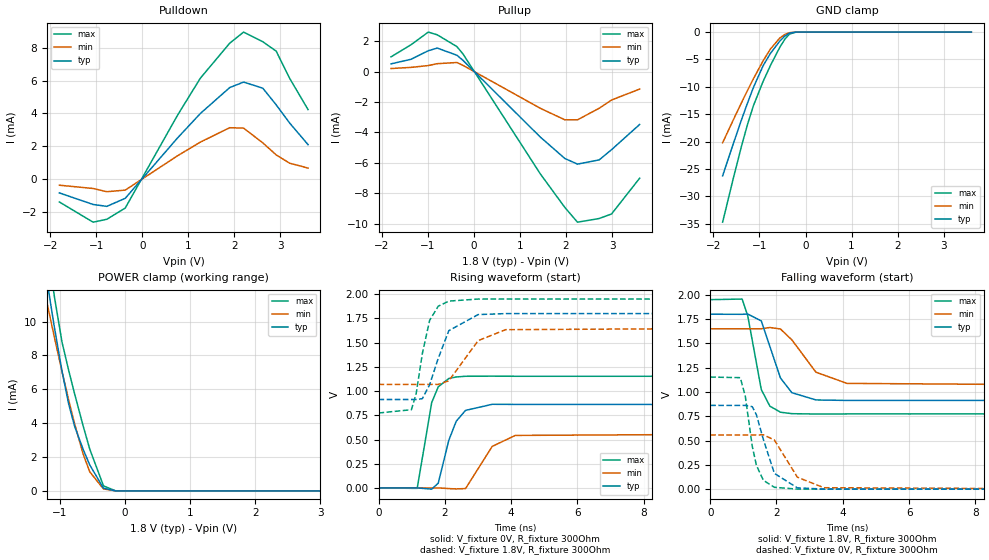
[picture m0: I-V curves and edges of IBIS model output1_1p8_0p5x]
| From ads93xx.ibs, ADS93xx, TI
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|   output1_1p8_0p5x Model
[Model]   output1_1p8_0p5x
Model_type   3-state
Polarity   Non-Inverting
Vmeas = 0.9
Vref = 0
Cref = 2pF
Rref = 100000
|   typ   min   max
C_comp   0.731pF   0.567pF   0.776pF
[Voltage Range]   1.8   1.65   1.95
[Temperature Range]   27   125   -40
[Pullup Reference]   1.8   1.65   1.95
[Pulldown Reference]   0   0   0
[Power Clamp Reference]   1.8   1.65   1.95
[GND Clamp Reference]   0   0   0
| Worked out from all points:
|   slope of the pulldown table from 0 to 0.27 V, typ, clamps not added: 300 ohm
|   slope of the pullup table from 0 to 0.27 V, typ, clamps not added: 316 ohm
|   GND clamp passes 1 mA (typ) near -0.48 V on its own axis
|   POWER clamp passes 1 mA (typ) near -0.47 V on its own axis
|   falling waveform, V_fixture 1.8V, R_fixture 300Ohm: 20-80 % time 538ps typ, 796ps min, 386ps max; typ from 1.8 V to 0.913 V
|   rising waveform, V_fixture 0V, R_fixture 300Ohm: 20-80 % time 449ps typ, 611ps min, 343ps max; typ from 0 V to 0.862 V
|   rising waveform, V_fixture 1.8V, R_fixture 300Ohm: 20-80 % time 550ps typ, 773ps min, 371ps max; typ from 0.913 V to 1.8 V
|   falling waveform, V_fixture 0V, R_fixture 300Ohm: 20-80 % time 446ps typ, 595ps min, 332ps max; typ from 0.862 V to 0 V
[Pulldown]
|   Voltage   I(typ)   I(min)   I(max)
-1.8V     -843.7uA   -375.7uA   -1.396mA
-1.066V   -1.55mA    -574.8uA   -2.628mA
-768.6mV  -1.664mA   -771uA     -2.45mA
-369mV    -1.173mA   -675.4uA   -1.765mA
765mV     2.497mA    1.413mA    3.879mA
1.262V    3.992mA    2.249mA    6.142mA
1.899V    5.57mA     3.127mA    8.272mA
2.201V    5.905mA    3.101mA    8.95mA
2.617V    5.535mA    2.206mA    8.365mA
2.909V    4.519mA    1.469mA    7.788mA
3.2V      3.415mA    967.5uA    6.139mA
3.6V      2.097mA    668uA      4.232mA
[GND Clamp]
|   Voltage   I(typ)   I(min)   I(max)
-1.8V     -26.25mA   -20.21mA   -34.72mA
-1.568V   -20.38mA   -16.03mA   -26.71mA
-1.39V    -16.01mA   -12.89mA   -20.83mA
-1.26V    -12.96mA   -10.66mA   -16.87mA
-1.13V    -10.09mA   -8.505mA   -13.41mA
-919.8mV  -6.124mA   -5.225mA   -8.988mA
-763.2mV  -3.905mA   -3.105mA   -6.125mA
-558mV    -1.639mA   -1.074mA   -2.766mA
-444.6mV  -687.9uA   -414.5uA   -1.249mA
-347.4mV  -177.3uA   -111.8uA   -351.2uA
-207mV    -3.81uA    -5.113uA   -4.887uA
3.6V      0A         0A         0A
[Pullup]
|   Voltage   I(typ)   I(min)   I(max)
-1.8V     519uA      210.2uA    977.4uA
-1.363V   819.6uA    287uA      1.78mA
-990mV    1.383mA    406.1uA    2.61mA
-795.6mV  1.559mA    529.3uA    2.431mA
-369mV    1.086mA    608uA      1.655mA
-239.4mV  758.6uA    424.4uA    1.183mA
1.445V    -4.308mA   -2.411mA   -6.737mA
1.975V    -5.711mA   -3.164mA   -8.933mA
2.25V     -6.083mA   -3.167mA   -9.906mA
2.72V     -5.805mA   -2.406mA   -9.664mA
2.99V     -5.13mA    -1.86mA    -9.363mA
3.6V      -3.47mA    -1.141mA   -7.008mA
[POWER Clamp]
|   Voltage   I(typ)   I(min)   I(max)
-1.8V     29.13mA    22.73mA    38.22mA
-1.217V   12.88mA    11.44mA    15.47mA
-1.13V    10.74mA    9.875mA    12.75mA
-1.087V   9.709mA    9.107mA    11.52mA
-968.4mV  7.078mA    7.058mA    8.793mA
-865.8mV  5.13mA     5.375mA    7.115mA
-774mV    3.808mA    3.958mA    5.725mA
-644.4mV  2.459mA    2.187mA    3.849mA
-541.8mV  1.531mA    1.127mA    2.464mA
-331.2mV  161.8uA    118.5uA    297.9uA
-142.2mV  415nA      1.1uA      356.8nA
3.6V      0A         0A         0A
[Ramp]
R_load = 300
|   typ   min   max
dV/dt_r   0.51693/4.48542e-10   0.334335/6.11186e-10   0.691708/3.43037e-10
dV/dt_f   0.532246/5.37805e-10   0.348342/7.95639e-10   0.705808/3.86079e-10
[Falling Waveform]
V_fixture = 1.8V
V_fixture_min = 1.65V
V_fixture_max = 1.95V
R_fixture = 300Ohm
C_fixture = 0F
|   Time   V(typ)   V(min)   V(max)
0s        1.8V       1.65V      1.95V
963.2ps   1.799V     1.65V      1.956V
1.134ns   1.802V     1.65V      1.782V
1.541ns   1.731V     1.65V      1.025V
1.8ns     1.469V     1.663V     853.6mV
2.119ns   1.144V     1.648V     791.5mV
2.463ns   992.3mV    1.536V     776.2mV
3.191ns   917.5mV    1.203V     772.6mV
4.126ns   912.5mV    1.088V     773.6mV
12.5ns    912.9mV    1.069V     773.7mV
[Rising Waveform]
V_fixture = 0V
V_fixture_min = 0V
V_fixture_max = 0V
R_fixture = 300Ohm
C_fixture = 0F
|   Time   V(typ)   V(min)   V(max)
0s        262.6nV    3.258uV    42.43nV
1.166ns   565.6uV    286.3uV    -4.253mV
1.604ns   -12.48mV   392.5uV    882.3mV
1.801ns   49.73mV    440.2uV    1.044V
2.119ns   491.6mV    -6.592mV   1.13V
2.341ns   687.7mV    -9.993mV   1.146V
2.624ns   800.6mV    -6.398mV   1.153V
3.429ns   863.7mV    429.2mV    1.154V
4.126ns   862.5mV    542.4mV    1.153V
12.5ns    861.6mV    557.2mV    1.153V
[Rising Waveform]
V_fixture = 1.8V
V_fixture_min = 1.65V
V_fixture_max = 1.95V
R_fixture = 300Ohm
C_fixture = 0F
|   Time   V(typ)   V(min)   V(max)
0s        913mV      1.069V     773.7mV
990.7ps   913.1mV    1.069V     807.8mV
1.134ns   913.2mV    1.069V     972.2mV
1.322ns   922.1mV    1.069V     1.389V
1.541ns   1.066V     1.069V     1.73V
1.8ns     1.337V     1.069V     1.876V
2.119ns   1.624V     1.106V     1.929V
3.005ns   1.79V      1.521V     1.95V
3.833ns   1.8V       1.634V     1.95V
12.5ns    1.8V       1.65V      1.95V
[Falling Waveform]
|Gnd
V_fixture = 0V
V_fixture_min = 0V
V_fixture_max = 0V
R_fixture = 300Ohm
C_fixture = 0F
|   Time   V(typ)   V(min)   V(max)
0s        861.6mV    557.2mV    1.153V
907.6ps   861.3mV    557.1mV    1.147V
1.059ns   861.2mV    557mV      954.8mV
1.268ns   848.3mV    557mV      443mV
1.394ns   765mV      557mV      244.5mV
1.604ns   510.6mV    558.5mV    90.31mV
1.936ns   161.7mV    505.2mV    18.14mV
2.63ns    12.45mV    122.5mV    -154.1uV
3.429ns   110.4uV    13.89mV    -934uV
12.5ns    265.7nV    3.109uV    41.91nV
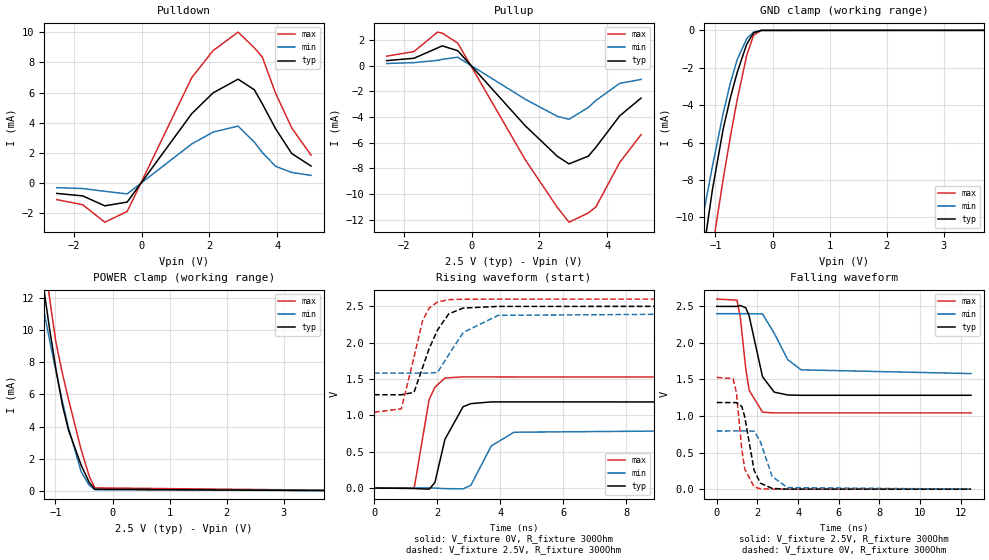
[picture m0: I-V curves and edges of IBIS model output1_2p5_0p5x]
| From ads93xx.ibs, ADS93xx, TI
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|   output1_2p5_0p5x Model
[Model]   output1_2p5_0p5x
Model_type   3-state
Polarity   Non-Inverting
Vmeas = 1.25
Vref = 0
Cref = 2pF
Rref = 100000
|   typ   min   max
C_comp   0.698pF   0.559pF   0.737pF
[Voltage Range]   2.5   2.4   2.6
[Temperature Range]   27   125   -40
[Pullup Reference]   2.5   2.4   2.6
[Pulldown Reference]   0   0   0
[Power Clamp Reference]   2.5   2.4   2.6
[GND Clamp Reference]   0   0   0
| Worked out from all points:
|   slope of the pulldown table from 0 to 0.375 V, typ, clamps not added: 301 ohm
|   slope of the pullup table from 0 to 0.375 V, typ, clamps not added: 318 ohm
|   GND clamp passes 1 mA (typ) near -0.49 V on its own axis
|   POWER clamp passes 1 mA (typ) near -0.48 V on its own axis
|   falling waveform, V_fixture 2.5V, R_fixture 300Ohm: 20-80 % time 574ps typ, 903ps min, 409ps max; typ from 2.5 V to 1.28 V
|   rising waveform, V_fixture 0V, R_fixture 300Ohm: 20-80 % time 457ps typ, 629ps min, 345ps max; typ from 0 V to 1.18 V
|   rising waveform, V_fixture 2.5V, R_fixture 300Ohm: 20-80 % time 653ps typ, 856ps min, 504ps max; typ from 1.28 V to 2.5 V
|   falling waveform, V_fixture 0V, R_fixture 300Ohm: 20-80 % time 453ps typ, 597ps min, 346ps max; typ from 1.18 V to 0 V
[Pulldown]
|   Voltage   I(typ)   I(min)   I(max)
-2.5V     -706.7uA   -326.9uA   -1.119mA
-1.735V   -870.5uA   -383.4uA   -1.458mA
-1.083V   -1.531mA   -565.4uA   -2.62mA
-422.5mV  -1.282mA   -739.7uA   -1.907mA
1.482V    4.596mA    2.586mA    6.992mA
2.112V    5.981mA    3.368mA    8.788mA
2.848V    6.889mA    3.77mA     10.02mA
3.328V    6.184mA    2.706mA    8.973mA
3.56V     5.263mA    2.023mA    8.374mA
3.958V    3.581mA    1.089mA    5.936mA
4.43V     1.946mA    688.1uA    3.652mA
5V        1.115mA    492.9uA    1.838mA
[GND Clamp]
|   Voltage   I(typ)   I(min)   I(max)
-2.5V     -44.39mA   -33.12mA   -59.46mA
-1.413V   -16.56mA   -13.29mA   -21.57mA
-1.285V   -13.54mA   -11.09mA   -17.6mA
-1.21V    -11.83mA   -9.823mA   -15.46mA
-1.052V   -8.501mA   -7.252mA   -11.64mA
-865mV    -5.281mA   -4.442mA   -7.963mA
-737.5mV  -3.589mA   -2.797mA   -5.676mA
-617.5mV  -2.236mA   -1.555mA   -3.679mA
-452.5mV  -743.8uA   -449.7uA   -1.342mA
-332.5mV  -131.9uA   -85.99uA   -263.4uA
-197.5mV  -2.745uA   -3.997uA   -3.249uA
5V        0A         0A         0A
[Pullup]
|   Voltage   I(typ)   I(min)   I(max)
-2.5V     381.6uA    158.4uA    726.9uA
-1.698V   564.8uA    223.7uA    1.085mA
-1V       1.368mA    401.6uA    2.603mA
-865mV    1.53mA     475.5uA    2.525mA
-407.5mV  1.155mA    646.2uA    1.752mA
1.587V    -4.695mA   -2.627mA   -7.343mA
2.533V    -7.072mA   -3.958mA   -11.06mA
2.877V    -7.66mA    -4.186mA   -12.2mA
3.447V    -7.055mA   -3.258mA   -11.48mA
3.672V    -6.354mA   -2.717mA   -11mA
4.37V     -3.923mA   -1.39mA    -7.552mA
5V        -2.538mA   -1.085mA   -5.385mA
[POWER Clamp]
|   Voltage   I(typ)   I(min)   I(max)
-2.5V     50.08mA    37.08mA    68.11mA
-1.292V   14.84mA    12.84mA    18.08mA
-1.248V   13.67mA    12.01mA    16.51mA
-1.202V   12.52mA    11.18mA    15mA
-1.113V   10.31mA    9.555mA    12.23mA
-992.5mV  7.585mA    7.466mA    9.256mA
-880mV    5.374mA    5.602mA    7.334mA
-775mV    3.82mA     3.973mA    5.74mA
-550mV    1.602mA    1.196mA    2.57mA
-407.5mV  524.1uA    345.2uA    909.1uA
-310mV    102.3uA    80.34uA    188.9uA
5V        0A         0A         0A
[Ramp]
R_load = 300
|   typ   min   max
dV/dt_r   0.710684/4.5657e-10   0.477432/6.29414e-10   0.917002/3.4523e-10
dV/dt_f   0.729763/5.74325e-10   0.491192/9.02866e-10   0.934183/4.09032e-10
[Falling Waveform]
V_fixture = 2.5V
V_fixture_min = 2.4V
V_fixture_max = 2.6V
R_fixture = 300Ohm
C_fixture = 0F
|   Time   V(typ)   V(min)   V(max)
0s        2.5V       2.4V       2.6V
996.2ps   2.499V     2.4V       2.585V
1.161ns   2.512V     2.4V       2.345V
1.429ns   2.481V     2.4V       1.641V
1.594ns   2.368V     2.4V       1.353V
2.249ns   1.539V     2.397V     1.053V
2.824ns   1.327V     2.133V     1.043V
3.49ns    1.288V     1.771V     1.043V
4.15ns    1.284V     1.632V     1.043V
12.5ns    1.284V     1.581V     1.043V
[Rising Waveform]
V_fixture = 0V
V_fixture_min = 0V
V_fixture_max = 0V
R_fixture = 300Ohm
C_fixture = 0F
|   Time   V(typ)   V(min)   V(max)
0s        185.4nV    3.337uV    25.93nV
1.273ns   -6.46mV    335uV      -355.7uV
1.747ns   -15.83mV   458.5uV    1.217V
1.929ns   75.11mV    -918.7uV   1.387V
2.249ns   671.4mV    -8.117mV   1.514V
2.824ns   1.119V     -11.53mV   1.529V
3.071ns   1.161V     38.38mV    1.529V
3.716ns   1.185V     577.7mV    1.529V
4.434ns   1.185V     767.8mV    1.528V
12.5ns    1.184V     795.7mV    1.528V
[Rising Waveform]
V_fixture = 2.5V
V_fixture_min = 2.4V
V_fixture_max = 2.6V
R_fixture = 300Ohm
C_fixture = 0F
|   Time   V(typ)   V(min)   V(max)
0s        1.284V     1.581V     1.043V
865.3ps   1.283V     1.581V     1.089V
1.267ns   1.316V     1.581V     1.8V
1.538ns   1.656V     1.581V     2.301V
1.747ns   1.918V     1.581V     2.477V
2.011ns   2.173V     1.59V      2.56V
2.368ns   2.396V     1.834V     2.592V
2.826ns   2.476V     2.14V      2.598V
3.937ns   2.499V     2.376V     2.599V
12.5ns    2.5V       2.4V       2.6V
[Falling Waveform]
|Gnd
V_fixture = 0V
V_fixture_min = 0V
V_fixture_max = 0V
R_fixture = 300Ohm
C_fixture = 0F
|   Time   V(typ)   V(min)   V(max)
0s        1.185V     795.7mV    1.528V
801.7ps   1.184V     796.1mV    1.513V
964.4ps   1.184V     796.2mV    1.327V
1.231ns   1.132V     796.4mV    548.6mV
1.374ns   992.6mV    796.5mV    277.5mV
1.839ns   256.5mV    794.5mV    30.06mV
2.148ns   81.42mV    645.8mV    6.216mV
2.724ns   10.15mV    173.3mV    315.9uV
3.471ns   614.1uV    21.48mV    291.8uV
12.5ns    1.223nV    3.1uV      7.163nV
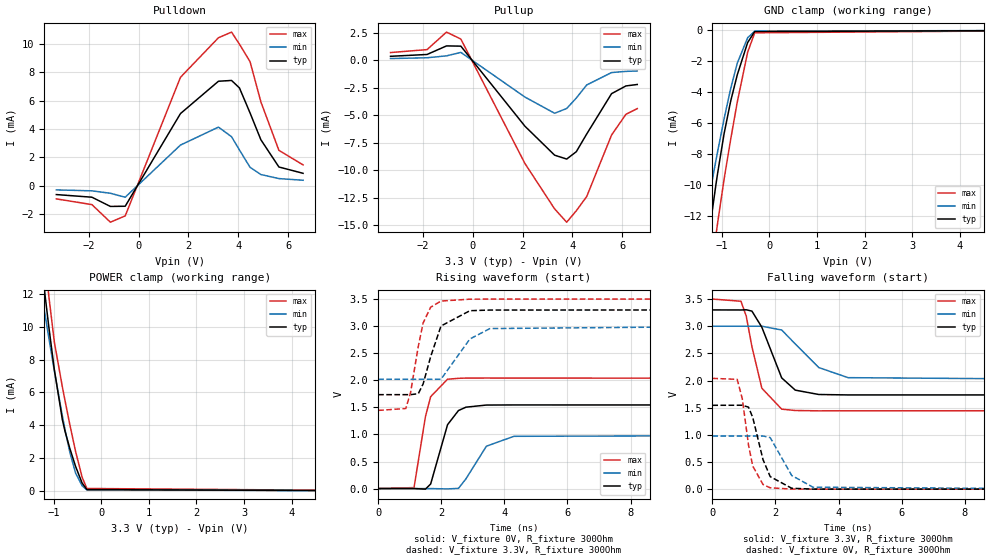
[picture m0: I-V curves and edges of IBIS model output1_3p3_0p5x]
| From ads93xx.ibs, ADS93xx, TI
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|   output1_3p3_0p5x Model
[Model]   output1_3p3_0p5x
Model_type   3-state
Polarity   Non-Inverting
Vmeas = 1.65
Vref = 0
Cref = 2pF
Rref = 100000
|   typ   min   max
C_comp   0.672pF   0.552pF   0.701pF
[Voltage Range]   3.3   3   3.5
[Temperature Range]   27   125   -40
[Pullup Reference]   3.3   3   3.5
[Pulldown Reference]   0   0   0
[Power Clamp Reference]   3.3   3   3.5
[GND Clamp Reference]   0   0   0
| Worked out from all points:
|   slope of the pulldown table from 0 to 0.495 V, typ, clamps not added: 303 ohm
|   slope of the pullup table from 0 to 0.495 V, typ, clamps not added: 320 ohm
|   GND clamp passes 1 mA (typ) near -0.49 V on its own axis
|   POWER clamp passes 1 mA (typ) near -0.48 V on its own axis
|   falling waveform, V_fixture 3.3V, R_fixture 300Ohm: 20-80 % time 634ps typ, 997ps min, 461ps max; typ from 3.3 V to 1.74 V
|   rising waveform, V_fixture 0V, R_fixture 300Ohm: 20-80 % time 478ps typ, 633ps min, 362ps max; typ from 0 V to 1.54 V
|   rising waveform, V_fixture 3.3V, R_fixture 300Ohm: 20-80 % time 488ps typ, 663ps min, 388ps max; typ from 1.74 V to 3.3 V
|   falling waveform, V_fixture 0V, R_fixture 300Ohm: 20-80 % time 431ps typ, 561ps min, 332ps max; typ from 1.54 V to 0 V
[Pulldown]
|   Voltage   I(typ)   I(min)   I(max)
-3.3V     -632.2uA   -302uA     -936.7uA
-1.874V   -818uA     -368uA     -1.34mA
-1.132V   -1.469mA   -539.8uA   -2.582mA
-537.9mV  -1.456mA   -820uA     -2.138mA
1.68V     5.087mA    2.863mA    7.648mA
3.204V    7.37mA     4.131mA    10.44mA
3.729V    7.425mA    3.454mA    10.84mA
4.046V    6.9mA      2.521mA    9.988mA
4.471V    5.137mA    1.294mA    8.757mA
4.907V    3.237mA    783.1uA    5.912mA
5.63V     1.315mA    496.8uA    2.491mA
6.6V      868.6uA    379.4uA    1.461mA
[GND Clamp]
|   Voltage   I(typ)   I(min)   I(max)
-3.3V     -65.43mA   -48.13mA   -88mA
-1.419V   -16.72mA   -13.4mA    -21.78mA
-1.34V    -14.82mA   -12.03mA   -19.27mA
-1.251V   -12.75mA   -10.51mA   -16.6mA
-1.122V   -9.915mA   -8.368mA   -13.21mA
-1.092V   -9.299mA   -7.887mA   -12.52mA
-953.7mV  -6.687mA   -5.727mA   -9.638mA
-815.1mV  -4.579mA   -3.766mA   -7.051mA
-676.5mV  -2.877mA   -2.123mA   -4.639mA
-458.7mV  -789uA     -478.5uA   -1.416mA
-310.2mV  -80.27uA   -56.11uA   -160.2uA
6.6V      0A         0A         0A
[Pullup]
|   Voltage   I(typ)   I(min)   I(max)
-3.3V     340.1uA    135.7uA    680.5uA
-1.835V   506uA      206.1uA    948.9uA
-1.053V   1.285mA    380uA      2.541mA
-478.5mV  1.263mA    695.5uA    1.908mA
2.095V    -6.018mA   -3.367mA   -9.411mA
3.284V    -8.648mA   -4.837mA   -13.53mA
3.769V    -9.001mA   -4.404mA   -14.74mA
4.155V    -8.331mA   -3.452mA   -13.7mA
4.571V    -6.727mA   -2.266mA   -12.41mA
5.57V     -3.053mA   -1.137mA   -6.814mA
6.145V    -2.355mA   -1.032mA   -4.935mA
6.6V      -2.222mA   -994uA     -4.413mA
[POWER Clamp]
|   Voltage   I(typ)   I(min)   I(max)
-3.3V     74.57mA    53.89mA    103mA
-1.241V   13.49mA    11.88mA    16.28mA
-1.171V   11.74mA    10.61mA    14mA
-1.102V   10.06mA    9.373mA    11.94mA
-983.4mV  7.392mA    7.311mA    9.076mA
-815.1mV  4.344mA    4.58mA     6.342mA
-755.7mV  3.594mA    3.689mA    5.454mA
-656.7mV  2.576mA    2.339mA    4.022mA
-537.9mV  1.498mA    1.095mA    2.414mA
-399.3mV  475.5uA    314.3uA    830.4uA
-300.3mV  81.22uA    66.3uA     149.3uA
6.6V      0A         0A         0A
[Ramp]
R_load = 300
|   typ   min   max
dV/dt_r   0.926181/4.77678e-10   0.587231/6.33037e-10   1.22401/3.625e-10
dV/dt_f   0.938833/6.3376e-10   0.58887/9.96938e-10   1.23355/4.60705e-10
[Falling Waveform]
V_fixture = 3.3V
V_fixture_min = 3V
V_fixture_max = 3.5V
R_fixture = 300Ohm
C_fixture = 0F
|   Time   V(typ)   V(min)   V(max)
0s        3.3V       3V         3.5V
907.2ps   3.299V     3V         3.46V
1.074ns   3.303V     3V         3.186V
1.254ns   3.278V     3V         2.624V
1.569ns   2.981V     3V         1.858V
2.198ns   2.048V     2.93V      1.473V
2.629ns   1.823V     2.673V     1.448V
3.373ns   1.743V     2.239V     1.442V
4.301ns   1.735V     2.053V     1.443V
12.5ns    1.735V     2.019V     1.444V
[Rising Waveform]
V_fixture = 0V
V_fixture_min = 0V
V_fixture_max = 0V
R_fixture = 300Ohm
C_fixture = 0F
|   Time   V(typ)   V(min)   V(max)
0s        256nV      3.162uV    8.412nV
1.136ns   797.2uV    298.3uV    18.14mV
1.498ns   -10.86mV   392.5uV    1.331V
1.663ns   85.15mV    435.3uV    1.698V
2.198ns   1.18V      -6.358mV   2.02V
2.545ns   1.442V     4.149mV    2.037V
2.783ns   1.504V     180.9mV    2.041V
3.429ns   1.543V     782.8mV    2.042V
4.301ns   1.545V     965.6mV    2.041V
12.5ns    1.544V     978.7mV    2.04V
[Rising Waveform]
V_fixture = 3.3V
V_fixture_min = 3V
V_fixture_max = 3.5V
R_fixture = 300Ohm
C_fixture = 0F
|   Time   V(typ)   V(min)   V(max)
0s        1.735V     2.019V     1.444V
874.7ps   1.735V     2.019V     1.479V
1.024ns   1.735V     2.019V     1.769V
1.271ns   1.753V     2.019V     2.627V
1.424ns   1.933V     2.019V     3.06V
1.663ns   2.437V     2.019V     3.35V
1.99ns    3.003V     2.02V      3.464V
2.907ns   3.286V     2.764V     3.499V
3.54ns    3.298V     2.956V     3.501V
12.5ns    3.3V       3V         3.5V
[Falling Waveform]
|Gnd
V_fixture = 0V
V_fixture_min = 0V
V_fixture_max = 0V
R_fixture = 300Ohm
C_fixture = 0F
|   Time   V(typ)   V(min)   V(max)
0s        1.544V     978.7mV    2.04V
787.3ps   1.545V     978.8mV    2.022V
948.3ps   1.545V     978.8mV    1.666V
1.145ns   1.51V      978.9mV    815.9mV
1.279ns   1.323V     978.9mV    426.9mV
1.605ns   544.9mV    978.9mV    85.97mV
1.834ns   230.5mV    949.1mV    24.33mV
2.514ns   16.86mV    252.5mV    1.155mV
3.189ns   651.9uV    35.94mV    -115.9uV
12.5ns    244nV      3.284uV    -5.42nV
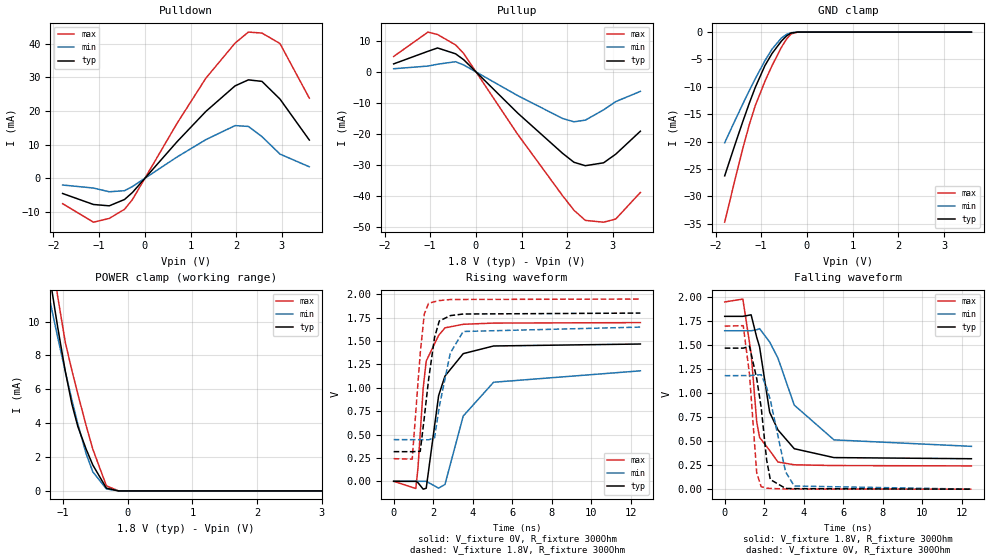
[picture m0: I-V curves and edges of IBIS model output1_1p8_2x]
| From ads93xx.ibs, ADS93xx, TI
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|   output1_1p8_2x Model
[Model]   output1_1p8_2x
Model_type   3-state
Polarity   Non-Inverting
Vmeas = 0.9
Vref = 0
Cref = 2pF
Rref = 100000
|   typ   min   max
C_comp   0.721pF   0.567pF   0.768pF
[Voltage Range]   1.8   1.65   1.95
[Temperature Range]   27   125   -40
[Pullup Reference]   1.8   1.65   1.95
[Pulldown Reference]   0   0   0
[Power Clamp Reference]   1.8   1.65   1.95
[GND Clamp Reference]   0   0   0
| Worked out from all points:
|   slope of the pulldown table from 0 to 0.27 V, typ, clamps not added: 64 ohm
|   slope of the pullup table from 0 to 0.27 V, typ, clamps not added: 67.3 ohm
|   GND clamp passes 1 mA (typ) near -0.48 V on its own axis
|   POWER clamp passes 1 mA (typ) near -0.47 V on its own axis
|   falling waveform, V_fixture 1.8V, R_fixture 300Ohm: 20-80 % time 980ps typ, 1.88ns min, 486ps max; typ from 1.8 V to 0.317 V
|   rising waveform, V_fixture 0V, R_fixture 300Ohm: 20-80 % time 880ps typ, 1.58ns min, 438ps max; typ from 0 V to 1.47 V
|   rising waveform, V_fixture 1.8V, R_fixture 300Ohm: 20-80 % time 521ps typ, 692ps min, 340ps max; typ from 0.317 V to 1.8 V
|   falling waveform, V_fixture 0V, R_fixture 300Ohm: 20-80 % time 533ps typ, 731ps min, 381ps max; typ from 1.47 V to 0 V
[Pulldown]
|   Voltage   I(typ)   I(min)   I(max)
-1.8V     -4.57mA    -2.043mA   -7.602mA
-1.125V   -7.841mA   -2.946mA   -13.11mA
-779.4mV  -8.241mA   -4.056mA   -11.99mA
-444.6mV  -6.348mA   -3.736mA   -9.27mA
-271.8mV  -4.267mA   -2.502mA   -6.378mA
705.6mV   10.85mA    6.306mA    16.33mA
1.337V    19.88mA    11.47mA    29.78mA
1.975V    27.47mA    15.64mA    40.19mA
2.266V    29.25mA    15.39mA    43.47mA
2.563V    28.8mA     12.36mA    43.18mA
2.957V    23.54mA    7.162mA    40.07mA
3.6V      11.34mA    3.38mA     23.81mA
[GND Clamp]
|   Voltage   I(typ)   I(min)   I(max)
-1.8V     -26.25mA   -20.21mA   -34.72mA
-1.568V   -20.38mA   -16.03mA   -26.71mA
-1.39V    -16.01mA   -12.89mA   -20.83mA
-1.26V    -12.96mA   -10.66mA   -16.87mA
-1.13V    -10.09mA   -8.505mA   -13.41mA
-919.8mV  -6.124mA   -5.225mA   -8.988mA
-763.2mV  -3.905mA   -3.105mA   -6.125mA
-558mV    -1.639mA   -1.074mA   -2.766mA
-444.6mV  -687.9uA   -414.5uA   -1.249mA
-347.4mV  -177.3uA   -111.8uA   -351.2uA
-207mV    -3.81uA    -5.113uA   -4.887uA
3.6V      0A         0A         0A
[Pullup]
|   Voltage   I(typ)   I(min)   I(max)
-1.8V     2.618mA    1.053mA    5mA
-1.049V   6.678mA    1.921mA    12.86mA
-838.8mV  7.746mA    2.511mA    12.07mA
-444.6mV  5.866mA    3.322mA    8.727mA
-266.4mV  3.953mA    2.267mA    5.968mA
916.2mV   -13.24mA   -7.602mA   -20.09mA
1.899V    -26.2mA    -14.97mA   -39.86mA
2.147V    -29.07mA   -16.03mA   -44.52mA
2.396V    -30.17mA   -15.49mA   -47.78mA
2.795V    -29.23mA   -12.18mA   -48.36mA
3.06V     -26.47mA   -9.535mA   -47.35mA
3.6V      -19.06mA   -6.231mA   -38.78mA
[POWER Clamp]
|   Voltage   I(typ)   I(min)   I(max)
-1.8V     29.13mA    22.73mA    38.22mA
-1.217V   12.88mA    11.44mA    15.47mA
-1.13V    10.74mA    9.875mA    12.75mA
-1.087V   9.709mA    9.107mA    11.52mA
-968.4mV  7.078mA    7.058mA    8.793mA
-865.8mV  5.13mA     5.375mA    7.115mA
-774mV    3.808mA    3.958mA    5.725mA
-644.4mV  2.459mA    2.187mA    3.849mA
-541.8mV  1.531mA    1.127mA    2.464mA
-331.2mV  161.8uA    118.5uA    297.9uA
-142.2mV  415.1nA    1.1uA      356.8nA
3.6V      0A         0A         0A
[Ramp]
R_load = 300
|   typ   min   max
dV/dt_r   0.881474/8.79422e-10   0.709144/1.57044e-09   1.01909/4.37245e-10
dV/dt_f   0.889777/9.79718e-10   0.7223/1.86885e-09   1.0247/4.85596e-10
[Falling Waveform]
V_fixture = 1.8V
V_fixture_min = 1.65V
V_fixture_max = 1.95V
R_fixture = 300Ohm
C_fixture = 0F
|   Time   V(typ)   V(min)   V(max)
0s        1.8V       1.65V      1.95V
918.7ps   1.8V       1.65V      1.98V
1.338ns   1.816V     1.65V      1.418V
1.622ns   1.582V     1.66V      701.9mV
1.767ns   1.482V     1.672V     539.7mV
2.278ns   801mV      1.533V     403mV
2.698ns   617.3mV    1.365V     283.2mV
3.524ns   421.3mV    875.4mV    253.8mV
5.537ns   328.9mV    513.4mV    246mV
12.5ns    317mV      446mV      242.2mV
[Rising Waveform]
V_fixture = 0V
V_fixture_min = 0V
V_fixture_max = 0V
R_fixture = 300Ohm
C_fixture = 0F
|   Time   V(typ)   V(min)   V(max)
0s        13.13uV    89.27uV    1.394uV
1.122ns   -274.7uV   -207uV     -76.9mV
1.233ns   -15.14mV   -236.5uV   144.7mV
1.497ns   -84.22mV   -306.3uV   999.3mV
1.65ns    -74.32mV   -346.5uV   1.287V
2.278ns   916mV      -73.37mV   1.561V
2.6ns     1.126V     -33.68mV   1.642V
3.524ns   1.366V     698.1mV    1.68V
5.064ns   1.448V     1.06V      1.693V
12.5ns    1.469V     1.182V     1.698V
[Rising Waveform]
V_fixture = 1.8V
V_fixture_min = 1.65V
V_fixture_max = 1.95V
R_fixture = 300Ohm
C_fixture = 0F
|   Time   V(typ)   V(min)   V(max)
0s        317mV      446mV      242.2mV
939.7ps   316.9mV    445.5mV    236.7mV
1.347ns   320.2mV    445.3mV    1.371V
1.552ns   681mV      445.1mV    1.789V
1.767ns   1.084V     443.7mV    1.904V
2.072ns   1.539V     465.9mV    1.922V
2.311ns   1.715V     796.9mV    1.934V
2.871ns   1.773V     1.373V     1.945V
3.524ns   1.79V      1.603V     1.946V
12.5ns    1.8V       1.65V      1.95V
[Falling Waveform]
|Gnd
V_fixture = 0V
V_fixture_min = 0V
V_fixture_max = 0V
R_fixture = 300Ohm
C_fixture = 0F
|   Time   V(typ)   V(min)   V(max)
0s        1.469V     1.182V     1.698V
939.7ps   1.469V     1.183V     1.703V
1.255ns   1.488V     1.183V     1.2V
1.622ns   1.152V     1.189V     168.4mV
1.85ns    848.7mV    1.192V     25.5mV
2.125ns   303.8mV    1.058V     10.43mV
2.311ns   100.3mV    929.4mV    7.537mV
3.083ns   7.868mV    181.4mV    1.65mV
3.524ns   5.443mV    32.63mV    1.573mV
12.5ns    14.54uV    87.89uV    728.2nV
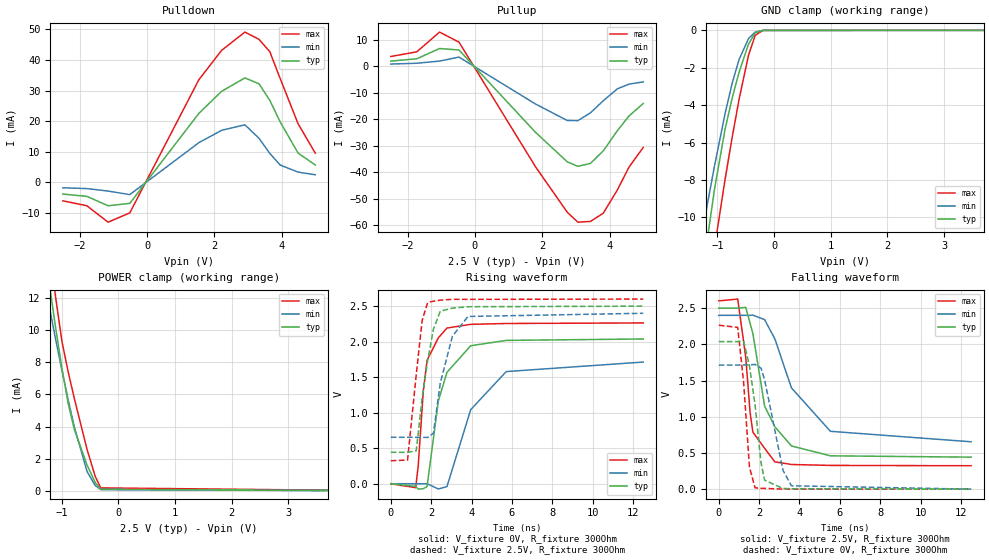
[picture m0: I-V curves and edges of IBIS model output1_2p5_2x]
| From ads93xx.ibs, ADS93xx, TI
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|   output1_2p5_2x Model
[Model]   output1_2p5_2x
Model_type   3-state
Polarity   Non-Inverting
Vmeas = 1.25
Vref = 0
Cref = 2pF
Rref = 100000
|   typ   min   max
C_comp   0.694pF   0.559pF   0.734pF
[Voltage Range]   2.5   2.4   2.6
[Temperature Range]   27   125   -40
[Pullup Reference]   2.5   2.4   2.6
[Pulldown Reference]   0   0   0
[Power Clamp Reference]   2.5   2.4   2.6
[GND Clamp Reference]   0   0   0
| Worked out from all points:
|   slope of the pulldown table from 0 to 0.375 V, typ, clamps not added: 64.2 ohm
|   slope of the pullup table from 0 to 0.375 V, typ, clamps not added: 67.6 ohm
|   GND clamp passes 1 mA (typ) near -0.49 V on its own axis
|   POWER clamp passes 1 mA (typ) near -0.48 V on its own axis
|   falling waveform, V_fixture 2.5V, R_fixture 300Ohm: 20-80 % time 1.07ns typ, 1.95ns min, 483ps max; typ from 2.5 V to 0.442 V
|   rising waveform, V_fixture 0V, R_fixture 300Ohm: 20-80 % time 916ps typ, 1.63ns min, 452ps max; typ from 0 V to 2.04 V
|   rising waveform, V_fixture 2.5V, R_fixture 300Ohm: 20-80 % time 617ps typ, 762ps min, 498ps max; typ from 0.442 V to 2.5 V
|   falling waveform, V_fixture 0V, R_fixture 300Ohm: 20-80 % time 510ps typ, 702ps min, 355ps max; typ from 2.04 V to 0 V
[Pulldown]
|   Voltage   I(typ)   I(min)   I(max)
-2.5V     -3.851mA   -1.79mA    -6.06mA
-1.788V   -4.596mA   -2.05mA    -7.666mA
-1.157V   -7.661mA   -2.861mA   -13.04mA
-512.5mV  -6.891mA   -4.022mA   -10.01mA
1.542V    22.56mA    12.98mA    33.57mA
2.217V    29.76mA    17.01mA    43.15mA
2.908V    34.13mA    18.8mA     49.12mA
3.328V    32.21mA    14.38mA    46.75mA
3.65V     26.77mA    9.419mA    42.67mA
3.958V    19.71mA    5.638mA    33.89mA
4.49V     9.542mA    3.327mA    19.12mA
5V        5.67mA     2.475mA    9.532mA
[GND Clamp]
|   Voltage   I(typ)   I(min)   I(max)
-2.5V     -44.39mA   -33.12mA   -59.46mA
-1.413V   -16.56mA   -13.29mA   -21.57mA
-1.285V   -13.54mA   -11.09mA   -17.6mA
-1.21V    -11.83mA   -9.823mA   -15.46mA
-1.052V   -8.501mA   -7.252mA   -11.64mA
-865mV    -5.281mA   -4.442mA   -7.963mA
-737.5mV  -3.589mA   -2.797mA   -5.676mA
-617.5mV  -2.236mA   -1.555mA   -3.679mA
-452.5mV  -743.8uA   -449.7uA   -1.342mA
-332.5mV  -131.9uA   -85.99uA   -263.4uA
-197.5mV  -2.745uA   -3.997uA   -3.249uA
5V        0A         0A         0A
[Pullup]
|   Voltage   I(typ)   I(min)   I(max)
-2.5V     1.909mA    791.3uA    3.641mA
-1.728V   2.78mA     1.1mA      5.406mA
-1.052V   6.653mA    1.915mA    12.85mA
-475mV    6.094mA    3.423mA    9.061mA
1.798V    -24.93mA   -14.26mA   -37.91mA
2.743V    -36.07mA   -20.49mA   -55.08mA
3.058V    -37.77mA   -20.55mA   -58.84mA
3.433V    -36.67mA   -17.59mA   -58.55mA
3.815V    -31.92mA   -13.02mA   -55.43mA
4.235V    -24.28mA   -8.516mA   -46.6mA
4.58V     -18.76mA   -6.765mA   -38.02mA
5V        -14.09mA   -5.933mA   -30.66mA
[POWER Clamp]
|   Voltage   I(typ)   I(min)   I(max)
-2.5V     50.08mA    37.08mA    68.11mA
-1.292V   14.84mA    12.84mA    18.08mA
-1.248V   13.67mA    12.01mA    16.51mA
-1.202V   12.52mA    11.18mA    15mA
-1.113V   10.31mA    9.555mA    12.23mA
-992.5mV  7.585mA    7.466mA    9.256mA
-880mV    5.374mA    5.602mA    7.334mA
-775mV    3.82mA     3.973mA    5.74mA
-550mV    1.602mA    1.196mA    2.57mA
-407.5mV  524.1uA    345.2uA    909.1uA
-310mV    102.4uA    80.34uA    188.9uA
5V        0A         0A         0A
[Ramp]
R_load = 300
|   typ   min   max
dV/dt_r   1.22301/9.18893e-10   1.02801/1.62704e-09   1.3582/4.52223e-10
dV/dt_f   1.23482/1.07633e-09   1.04726/1.95145e-09   1.36584/4.82033e-10
[Falling Waveform]
V_fixture = 2.5V
V_fixture_min = 2.4V
V_fixture_max = 2.6V
R_fixture = 300Ohm
C_fixture = 0F
|   Time   V(typ)   V(min)   V(max)
0s        2.5V       2.4V       2.6V
940.9ps   2.5V       2.4V       2.625V
1.339ns   2.51V      2.4V       1.82V
1.552ns   2.29V      2.4V       1.064V
1.691ns   2.149V     2.403V     788.2mV
2.273ns   1.147V     2.341V     563.9mV
2.78ns    861.6mV    2.075V     377.2mV
3.602ns   596.4mV    1.398V     340.7mV
5.533ns   460.5mV    798.8mV    328.1mV
12.5ns    441.9mV    654.3mV    323.6mV
[Rising Waveform]
V_fixture = 0V
V_fixture_min = 0V
V_fixture_max = 0V
R_fixture = 300Ohm
C_fixture = 0F
|   Time   V(typ)   V(min)   V(max)
0s        14.99uV    101.4uV    1.25uV
1.231ns   -36.87mV   -604.6uV   -55.66mV
1.356ns   -76.78mV   -676.5uV   246.8mV
1.61ns    -69.78mV   -822.4uV   1.309V
1.795ns   -40.03mV   -928.5uV   1.739V
2.356ns   1.169V     -73.95mV   2.055V
2.78ns    1.568V     -40.83mV   2.192V
3.957ns   1.943V     1.043V     2.244V
5.716ns   2.018V     1.579V     2.256V
12.5ns    2.038V     1.713V     2.264V
[Rising Waveform]
V_fixture = 2.5V
V_fixture_min = 2.4V
V_fixture_max = 2.6V
R_fixture = 300Ohm
C_fixture = 0F
|   Time   V(typ)   V(min)   V(max)
0s        441.9mV    654.3mV    323.6mV
829.5ps   441.9mV    653.5mV    333mV
1.261ns   463.7mV    653mV      1.54V
1.552ns   1.21V      652.7mV    2.3V
1.825ns   1.731V     651.2mV    2.552V
2.111ns   2.176V     710.5mV    2.57V
2.448ns   2.428V     1.415V     2.585V
3.05ns    2.472V     2.077V     2.596V
3.822ns   2.492V     2.355V     2.596V
12.5ns    2.5V       2.4V       2.6V
[Falling Waveform]
|Gnd
V_fixture = 0V
V_fixture_min = 0V
V_fixture_max = 0V
R_fixture = 300Ohm
C_fixture = 0F
|   Time   V(typ)   V(min)   V(max)
0s        2.038V     1.713V     2.264V
940.9ps   2.038V     1.714V     2.234V
1.231ns   2.043V     1.715V     1.483V
1.522ns   1.702V     1.715V     303.2mV
1.8ns     1.164V     1.723V     18.57mV
2.094ns   362.6mV    1.671V     10.77mV
2.273ns   124mV      1.51V      10.45mV
3.183ns   9.401mV    259.1mV    1.5mV
3.602ns   6.521mV    46.75mV    1.433mV
12.5ns    14.99uV    101.3uV    1.391uV
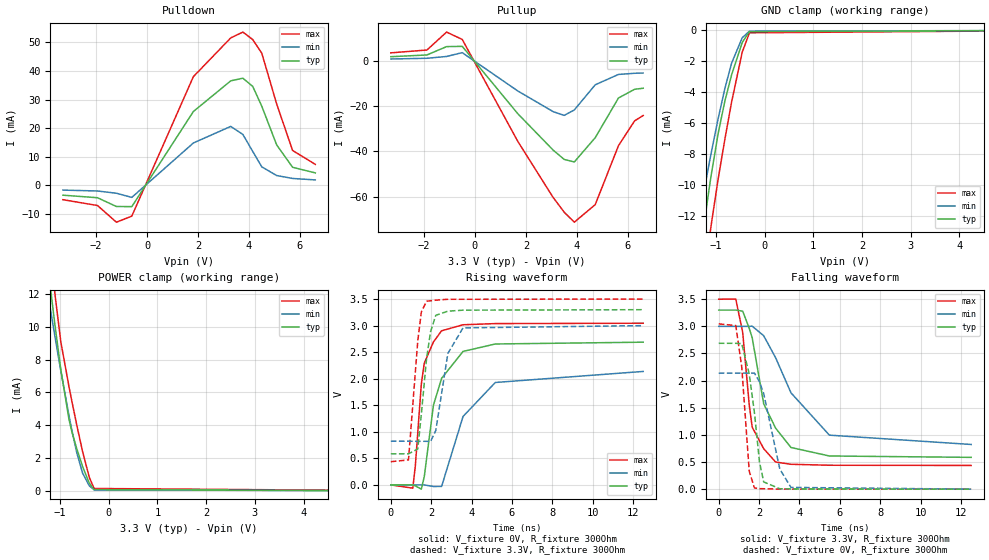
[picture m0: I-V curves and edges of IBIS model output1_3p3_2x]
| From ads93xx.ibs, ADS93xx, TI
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|   output1_3p3_2x Model
[Model]   output1_3p3_2x
Model_type   3-state
Polarity   Non-Inverting
Vmeas = 1.5
Vref = 0
Cref = 2pF
Rref = 100000
|   typ   min   max
C_comp   0.669pF   0.554pF   0.698pF
[Voltage Range]   3.3   3   3.5
[Temperature Range]   27   125   -40
[Pullup Reference]   3.3   3   3.5
[Pulldown Reference]   0   0   0
[Power Clamp Reference]   3.3   3   3.5
[GND Clamp Reference]   0   0   0
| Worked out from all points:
|   slope of the pulldown table from 0 to 0.495 V, typ, clamps not added: 64.5 ohm
|   slope of the pullup table from 0 to 0.495 V, typ, clamps not added: 68 ohm
|   GND clamp passes 1 mA (typ) near -0.49 V on its own axis
|   POWER clamp passes 1 mA (typ) near -0.48 V on its own axis
|   falling waveform, V_fixture 3.3V, R_fixture 300Ohm: 20-80 % time 1.13ns typ, 1.96ns min, 533ps max; typ from 3.3 V to 0.586 V
|   rising waveform, V_fixture 0V, R_fixture 300Ohm: 20-80 % time 962ps typ, 1.66ns min, 493ps max; typ from 0 V to 2.69 V
|   rising waveform, V_fixture 3.3V, R_fixture 300Ohm: 20-80 % time 449ps typ, 588ps min, 361ps max; typ from 0.586 V to 3.3 V
|   falling waveform, V_fixture 0V, R_fixture 300Ohm: 20-80 % time 512ps typ, 710ps min, 356ps max; typ from 2.69 V to 0 V
[Pulldown]
|   Voltage   I(typ)   I(min)   I(max)
-3.3V     -3.435mA   -1.662mA   -5.013mA
-1.944V   -4.325mA   -1.969mA   -7.04mA
-1.201V   -7.398mA   -2.756mA   -12.88mA
-597.3mV  -7.433mA   -4.215mA   -10.76mA
1.818V    25.82mA    14.82mA    38.01mA
3.284V    36.55mA    20.61mA    51.56mA
3.759V    37.47mA    17.81mA    53.59mA
4.145V    34.62mA    11.87mA    50.98mA
4.501V    27.68mA    6.474mA    46.21mA
5.085V    14.14mA    3.43mA     28.44mA
5.709V    6.32mA     2.414mA    12.2mA
6.6V      4.355mA    1.897mA    7.348mA
[GND Clamp]
|   Voltage   I(typ)   I(min)   I(max)
-3.3V     -65.43mA   -48.13mA   -88mA
-1.419V   -16.72mA   -13.4mA    -21.78mA
-1.34V    -14.82mA   -12.03mA   -19.27mA
-1.251V   -12.75mA   -10.51mA   -16.6mA
-1.122V   -9.915mA   -8.368mA   -13.21mA
-1.092V   -9.299mA   -7.887mA   -12.52mA
-953.7mV  -6.687mA   -5.727mA   -9.638mA
-815.1mV  -4.579mA   -3.766mA   -7.051mA
-676.5mV  -2.877mA   -2.123mA   -4.639mA
-458.7mV  -789uA     -478.5uA   -1.416mA
-310.2mV  -80.27uA   -56.11uA   -160.2uA
6.6V      0A         0A         0A
[Pullup]
|   Voltage   I(typ)   I(min)   I(max)
-3.3V     1.698mA    677.6uA    3.397mA
-1.884V   2.463mA    1.005mA    4.645mA
-1.112V   6.146mA    1.804mA    12.55mA
-498.3mV  6.257mA    3.481mA    9.303mA
1.68V     -23.43mA   -13.41mA   -35.62mA
3.066V    -39.48mA   -22.52mA   -60.37mA
3.501V    -43.61mA   -24.17mA   -66.89mA
3.897V    -44.72mA   -21.78mA   -71.28mA
4.719V    -34mA      -10.68mA   -63.52mA
5.63V     -16.51mA   -6.126mA   -37.52mA
6.263V    -12.66mA   -5.613mA   -26.6mA
6.6V      -12.21mA   -5.49mA    -24.22mA
[POWER Clamp]
|   Voltage   I(typ)   I(min)   I(max)
-3.3V     74.57mA    53.89mA    103mA
-1.241V   13.49mA    11.88mA    16.28mA
-1.171V   11.74mA    10.61mA    14mA
-1.102V   10.06mA    9.372mA    11.94mA
-983.4mV  7.392mA    7.311mA    9.076mA
-815.1mV  4.344mA    4.58mA     6.342mA
-755.7mV  3.594mA    3.689mA    5.454mA
-656.7mV  2.576mA    2.339mA    4.022mA
-537.9mV  1.498mA    1.095mA    2.414mA
-399.3mV  475.5uA    314.3uA    830.4uA
-300.3mV  81.22uA    66.3uA     149.3uA
6.6V      0A         0A         0A
[Ramp]
R_load = 300
|   typ   min   max
dV/dt_r   1.61251/9.61563e-10   1.28224/1.66045e-09   1.82726/4.93248e-10
dV/dt_f   1.6284/1.13543e-09   1.3058/1.96151e-09   1.83781/5.33312e-10
[Falling Waveform]
V_fixture = 3.3V
V_fixture_min = 3V
V_fixture_max = 3.5V
R_fixture = 300Ohm
C_fixture = 0F
|   Time   V(typ)   V(min)   V(max)
0s        3.3V       3V         3.5V
844.3ps   3.3V       3V         3.503V
1.188ns   3.28V      3V         2.886V
1.511ns   2.963V     3V         1.552V
1.658ns   2.789V     3.003V     1.141V
2.227ns   1.573V     2.827V     746mV
2.818ns   1.124V     2.421V     499.9mV
3.577ns   768.3mV    1.776V     458.5mV
5.48ns    611.5mV    995.3mV    440.8mV
12.5ns    586mV      823.5mV    437mV
[Rising Waveform]
V_fixture = 0V
V_fixture_min = 0V
V_fixture_max = 0V
R_fixture = 300Ohm
C_fixture = 0F
|   Time   V(typ)   V(min)   V(max)
0s        14.71uV    92.21uV    2.136uV
1.089ns   -301.7uV   -75.49uV   -61.25mV
1.216ns   -18.05mV   -95.13uV   363mV
1.511ns   -80.16mV   -140.5uV   1.9V
1.658ns   157.3mV    -163.2uV   2.294V
2.111ns   1.502V     -29.42mV   2.693V
2.516ns   2.007V     -28.38mV   2.903V
3.577ns   2.514V     1.289V     3.016V
5.174ns   2.654V     1.929V     3.038V
12.5ns    2.688V     2.137V     3.045V
[Rising Waveform]
V_fixture = 3.3V
V_fixture_min = 3V
V_fixture_max = 3.5V
R_fixture = 300Ohm
C_fixture = 0F
|   Time   V(typ)   V(min)   V(max)
0s        586mV      823.4mV    437mV
875.3ps   585.9mV    822.3mV    470.9mV
1.335ns   675.2mV    821.7mV    2.71V
1.511ns   1.329V     821.5mV    3.255V
1.769ns   2.374V     821.1mV    3.459V
1.968ns   2.885V     817.9mV    3.468V
2.227ns   3.194V     1.024V     3.479V
2.825ns   3.272V     2.476V     3.496V
3.577ns   3.291V     2.957V     3.496V
12.5ns    3.3V       3V         3.5V
[Falling Waveform]
|Gnd
V_fixture = 0V
V_fixture_min = 0V
V_fixture_max = 0V
R_fixture = 300Ohm
C_fixture = 0F
|   Time   V(typ)   V(min)   V(max)
0s        2.688V     2.137V     3.045V
844.3ps   2.688V     2.138V     3.016V
1.139ns   2.682V     2.139V     2.255V
1.511ns   2.122V     2.139V     331.4mV
1.769ns   1.406V     2.138V     21.98mV
2.02ns    499.4mV    1.977V     9.794mV
2.227ns   133.4mV    1.764V     7.909mV
3.024ns   7.952mV    370.2mV    1.65mV
3.577ns   4.003mV    32.53mV    1.554mV
12.5ns    13.82uV    92.85uV    1.43uV
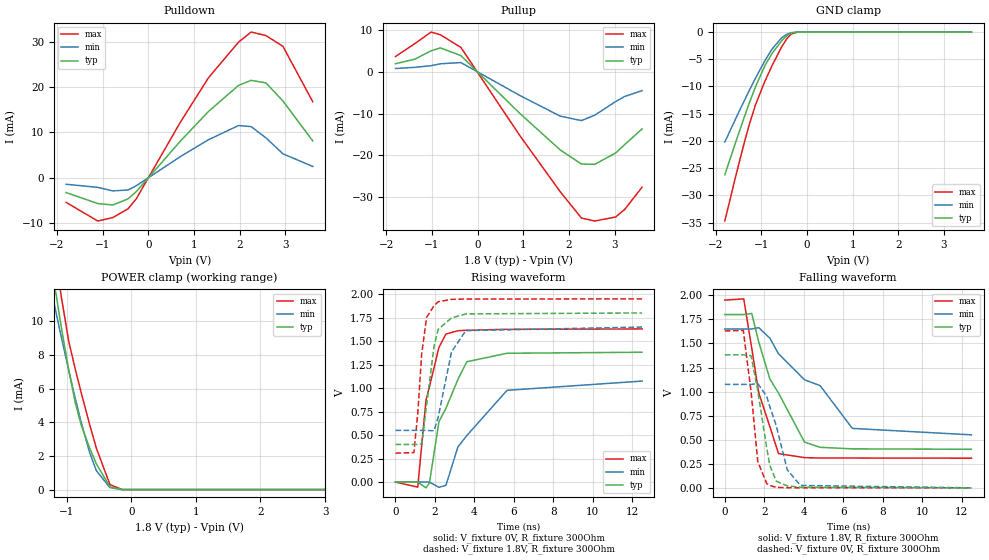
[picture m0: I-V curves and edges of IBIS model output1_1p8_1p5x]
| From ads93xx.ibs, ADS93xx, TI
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|   output1_1p8_1p5x Model
[Model]   output1_1p8_1p5x
Model_type   3-state
Polarity   Non-Inverting
Vmeas = 0.9
Vref = 0
Cref = 2pF
Rref = 100000
|   typ   min   max
C_comp   0.727pF   0.567pF   0.772pF
[Voltage Range]   1.8   1.65   1.95
[Temperature Range]   27   125   -40
[Pullup Reference]   1.8   1.65   1.95
[Pulldown Reference]   0   0   -0
[Power Clamp Reference]   1.8   1.65   1.95
[GND Clamp Reference]   0   0   0
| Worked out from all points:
|   slope of the pulldown table from 0 to 0.27 V, typ, clamps not added: 85.5 ohm
|   slope of the pullup table from 0 to 0.27 V, typ, clamps not added: 90 ohm
|   GND clamp passes 1 mA (typ) near -0.48 V on its own axis
|   POWER clamp passes 1 mA (typ) near -0.47 V on its own axis
|   falling waveform, V_fixture 1.8V, R_fixture 300Ohm: 20-80 % time 1.84ns typ, 3.07ns min, 1.08ns max; typ from 1.8 V to 0.401 V
|   rising waveform, V_fixture 0V, R_fixture 300Ohm: 20-80 % time 1.29ns typ, 2.19ns min, 767ps max; typ from 0 V to 1.38 V
|   rising waveform, V_fixture 1.8V, R_fixture 300Ohm: 20-80 % time 521ps typ, 691ps min, 366ps max; typ from 0.401 V to 1.8 V
|   falling waveform, V_fixture 0V, R_fixture 300Ohm: 20-80 % time 659ps typ, 865ps min, 503ps max; typ from 1.38 V to 0 V
[Pulldown]
|   Voltage   I(typ)   I(min)   I(max)
-1.8V     -3.319mA   -1.485mA   -5.499mA
-1.109V   -5.752mA   -2.17mA    -9.618mA
-779.4mV  -6.068mA   -2.95mA    -8.861mA
-444.6mV  -4.713mA   -2.757mA   -6.919mA
-266.4mV  -3.131mA   -1.821mA   -4.731mA
700.2mV   8.055mA    4.642mA    12.24mA
1.316V    14.62mA    8.37mA     22.09mA
1.975V    20.41mA    11.53mA    29.98mA
2.25V     21.52mA    11.28mA    32.22mA
2.574V    20.97mA    8.804mA    31.44mA
2.947V    16.95mA    5.259mA    29.06mA
3.6V      8.111mA    2.47mA     16.78mA
[GND Clamp]
|   Voltage   I(typ)   I(min)   I(max)
-1.8V     -26.25mA   -20.21mA   -34.72mA
-1.568V   -20.38mA   -16.03mA   -26.71mA
-1.39V    -16.01mA   -12.89mA   -20.83mA
-1.26V    -12.96mA   -10.66mA   -16.87mA
-1.13V    -10.09mA   -8.505mA   -13.41mA
-919.8mV  -6.124mA   -5.225mA   -8.988mA
-763.2mV  -3.905mA   -3.105mA   -6.125mA
-558mV    -1.639mA   -1.074mA   -2.766mA
-444.6mV  -687.9uA   -414.5uA   -1.249mA
-347.4mV  -177.3uA   -111.8uA   -351.2uA
-207mV    -3.81uA    -5.113uA   -4.887uA
3.6V      0A         0A         0A
[Pullup]
|   Voltage   I(typ)   I(min)   I(max)
-1.8V     1.913mA    771.1uA    3.637mA
-1.373V   3.011mA    1.045mA    6.728mA
-1.022V   4.996mA    1.444mA    9.481mA
-817.2mV  5.69mA     1.895mA    8.828mA
-369mV    3.865mA    2.192mA    5.815mA
927mV     -10mA      -5.695mA   -15.32mA
1.807V    -18.68mA   -10.61mA   -28.66mA
2.272V    -22.05mA   -11.67mA   -34.95mA
2.563V    -22.12mA   -10.38mA   -35.66mA
3.022V    -19.4mA    -7.122mA   -34.7mA
3.222V    -17.37mA   -5.899mA   -32.86mA
3.6V      -13.68mA   -4.518mA   -27.57mA
[POWER Clamp]
|   Voltage   I(typ)   I(min)   I(max)
-1.8V     29.13mA    22.73mA    38.22mA
-1.217V   12.88mA    11.44mA    15.47mA
-1.13V    10.74mA    9.875mA    12.75mA
-1.087V   9.709mA    9.107mA    11.52mA
-968.4mV  7.078mA    7.058mA    8.793mA
-865.8mV  5.13mA     5.375mA    7.115mA
-774mV    3.808mA    3.958mA    5.725mA
-644.4mV  2.459mA    2.187mA    3.849mA
-541.8mV  1.531mA    1.127mA    2.464mA
-331.2mV  161.8uA    118.5uA    297.9uA
-142.2mV  415.1nA    1.1uA      356.8nA
3.6V      0A         0A         0A
[Ramp]
R_load = 300
|   typ   min   max
dV/dt_r   0.829484/1.28858e-09   0.64474/2.19259e-09   0.977817/7.66388e-10
dV/dt_f   0.83964/1.83516e-09   0.659695/3.06827e-09   0.984997/1.08006e-09
[Falling Waveform]
V_fixture = 1.8V
V_fixture_min = 1.65V
V_fixture_max = 1.95V
R_fixture = 300Ohm
C_fixture = 0F
|   Time   V(typ)   V(min)   V(max)
0s        1.8V       1.65V      1.95V
957.9ps   1.8V       1.65V      1.963V
1.366ns   1.811V     1.65V      1.449V
1.716ns   1.517V     1.664V     990.5mV
2.283ns   1.131V     1.555V     634.8mV
2.723ns   983.9mV    1.392V     355.9mV
4.041ns   474.9mV    1.122V     313.8mV
4.828ns   421.1mV    1.062V     310.1mV
6.465ns   404.9mV    617.5mV    309.6mV
12.5ns    400.6mV    550.4mV    308.3mV
[Rising Waveform]
V_fixture = 0V
V_fixture_min = 0V
V_fixture_max = 0V
R_fixture = 300Ohm
C_fixture = 0F
|   Time   V(typ)   V(min)   V(max)
0s        -859.4nV   55.54uV    -71.41nV
1.127ns   -42.95uV   36.44uV    -53.93mV
1.545ns   -61.52mV   29.35uV    868.4mV
1.72ns    -10.52mV   26.38uV    1.013V
2.201ns   642mV      -55.81mV   1.433V
2.555ns   784.8mV    -35.11mV   1.575V
3.165ns   1.093V     374.2mV    1.611V
3.616ns   1.281V     495.2mV    1.616V
5.654ns   1.371V     976.3mV    1.626V
12.5ns    1.382V     1.075V     1.63V
[Rising Waveform]
V_fixture = 1.8V
V_fixture_min = 1.65V
V_fixture_max = 1.95V
R_fixture = 300Ohm
C_fixture = 0F
|   Time   V(typ)   V(min)   V(max)
0s        400.6mV    550.4mV    308.3mV
934.8ps   400.7mV    550mV      313.5mV
1.127ns   400.6mV    549.9mV    727.4mV
1.331ns   406.8mV    549.8mV    1.371V
1.579ns   822.4mV    549.7mV    1.754V
1.956ns   1.446V     546mV      1.878V
2.16ns    1.625V     686.4mV    1.919V
2.841ns   1.747V     1.387V     1.945V
3.567ns   1.79V      1.612V     1.948V
12.5ns    1.8V       1.65V      1.95V
[Falling Waveform]
|Gnd
V_fixture = 0V
V_fixture_min = 0V
V_fixture_max = 0V
R_fixture = 300Ohm
C_fixture = 0F
|   Time   V(typ)   V(min)   V(max)
0s        1.382V     1.075V     1.63V
934.8ps   1.382V     1.075V     1.635V
1.331ns   1.372V     1.075V     999.3mV
1.669ns   1.011V     1.082V     275.8mV
2.124ns   413.5mV    950.8mV    44.13mV
2.283ns   231.5mV    841.9mV    25.28mV
2.605ns   69.87mV    647.4mV    5.206mV
3.165ns   20.86mV    187.9mV    1.439mV
3.832ns   6.644mV    24.87mV    1.336mV
12.5ns    -457.3nV   55.5uV     -106.5nV
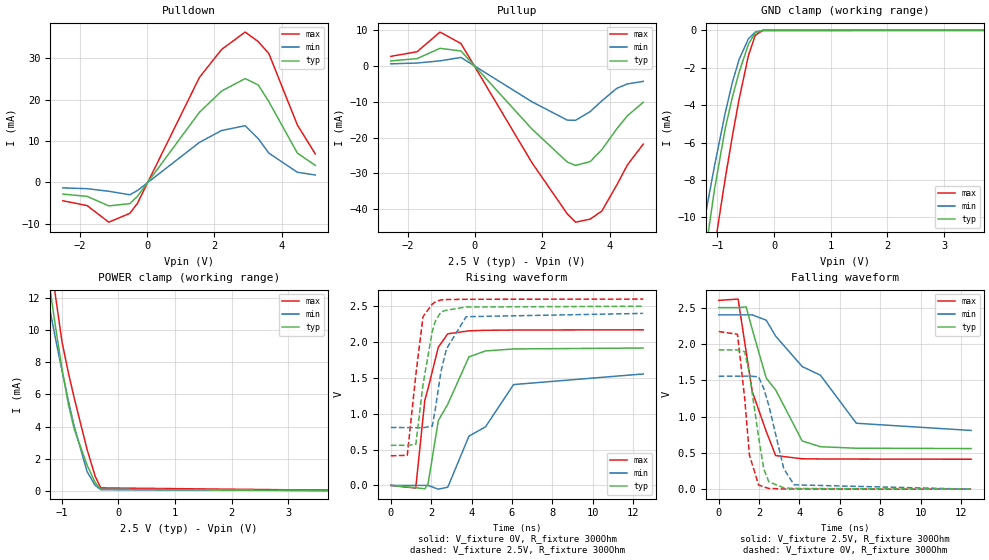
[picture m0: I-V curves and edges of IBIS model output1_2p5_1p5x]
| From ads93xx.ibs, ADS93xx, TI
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|   output1_2p5_1p5x Model
[Model]   output1_2p5_1p5x
Model_type   3-state
Polarity   Non-Inverting
Vmeas = 1.25
Vref = 0
Cref = 2pF
Rref = 100000
|   typ   min   max
C_comp   0.698pF   0.559pF   0.734pF
[Voltage Range]   2.5   2.4   2.6
[Temperature Range]   27   125   -40
[Pullup Reference]   2.5   2.4   2.6
[Pulldown Reference]   0   0   0
[Power Clamp Reference]   2.5   2.4   2.6
[GND Clamp Reference]   0   0   0
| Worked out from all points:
|   slope of the pulldown table from 0 to 0.375 V, typ, clamps not added: 85.8 ohm
|   slope of the pullup table from 0 to 0.375 V, typ, clamps not added: 90.5 ohm
|   GND clamp passes 1 mA (typ) near -0.49 V on its own axis
|   POWER clamp passes 1 mA (typ) near -0.48 V on its own axis
|   falling waveform, V_fixture 2.5V, R_fixture 300Ohm: 20-80 % time 1.84ns typ, 3.06ns min, 1.09ns max; typ from 2.5 V to 0.559 V
|   rising waveform, V_fixture 0V, R_fixture 300Ohm: 20-80 % time 1.32ns typ, 2.28ns min, 776ps max; typ from 0 V to 1.92 V
|   rising waveform, V_fixture 2.5V, R_fixture 300Ohm: 20-80 % time 620ps typ, 773ps min, 500ps max; typ from 0.559 V to 2.5 V
|   falling waveform, V_fixture 0V, R_fixture 300Ohm: 20-80 % time 596ps typ, 805ps min, 424ps max; typ from 1.92 V to 0 V
[Pulldown]
|   Voltage   I(typ)   I(min)   I(max)
-2.5V     -2.799mA   -1.3mA     -4.403mA
-1.78V    -3.349mA   -1.494mA   -5.571mA
-1.135V   -5.647mA   -2.118mA   -9.58mA
-512.5mV  -5.103mA   -2.96mA    -7.445mA
-287.5mV  -3.365mA   -1.957mA   -5.072mA
1.558V    16.96mA    9.683mA    25.38mA
2.217V    22.07mA    12.55mA    32.11mA
2.915V    25.08mA    13.71mA    36.3mA
3.305V    23.55mA    10.57mA    34.01mA
3.62V     19.51mA    7.092mA    31.11mA
4.468V    7.088mA    2.472mA    13.86mA
5V        4.135mA    1.812mA    6.903mA
[GND Clamp]
|   Voltage   I(typ)   I(min)   I(max)
-2.5V     -44.39mA   -33.12mA   -59.46mA
-1.413V   -16.56mA   -13.29mA   -21.57mA
-1.285V   -13.54mA   -11.09mA   -17.6mA
-1.21V    -11.83mA   -9.823mA   -15.46mA
-1.052V   -8.501mA   -7.252mA   -11.64mA
-865mV    -5.281mA   -4.442mA   -7.963mA
-737.5mV  -3.589mA   -2.797mA   -5.676mA
-617.5mV  -2.236mA   -1.555mA   -3.679mA
-452.5mV  -743.8uA   -449.7uA   -1.342mA
-332.5mV  -131.9uA   -85.99uA   -263.4uA
-197.5mV  -2.745uA   -3.997uA   -3.249uA
5V        0A         0A         0A
[Pullup]
|   Voltage   I(typ)   I(min)   I(max)
-2.5V     1.398mA    579.8uA    2.665mA
-1.72V    2.045mA    809.4uA    3.958mA
-1.038V   4.91mA     1.422mA    9.448mA
-415mV    4.173mA    2.36mA     6.253mA
1.692V    -17.6mA    -9.997mA   -27mA
2.743V    -26.83mA   -15.13mA   -41.3mA
2.99V     -27.78mA   -15.19mA   -43.63mA
3.425V    -26.71mA   -12.74mA   -42.77mA
3.77V     -23.38mA   -9.758mA   -40.53mA
4.213V    -17.58mA   -6.266mA   -33.27mA
4.527V    -13.94mA   -5.029mA   -27.7mA
5V        -10.16mA   -4.308mA   -21.83mA
[POWER Clamp]
|   Voltage   I(typ)   I(min)   I(max)
-2.5V     50.08mA    37.08mA    68.11mA
-1.292V   14.84mA    12.84mA    18.08mA
-1.248V   13.67mA    12.01mA    16.51mA
-1.202V   12.52mA    11.18mA    15mA
-1.113V   10.31mA    9.555mA    12.23mA
-992.5mV  7.585mA    7.466mA    9.256mA
-880mV    5.374mA    5.602mA    7.334mA
-775mV    3.82mA     3.973mA    5.74mA
-550mV    1.602mA    1.196mA    2.57mA
-407.5mV  524.1uA    345.2uA    909.1uA
-310mV    102.4uA    80.34uA    188.9uA
5V        0A         0A         0A
[Ramp]
R_load = 300
|   typ   min   max
dV/dt_r   1.15009/1.32314e-09   0.933106/2.27831e-09   1.3028/7.76475e-10
dV/dt_f   1.16455/1.83972e-09   0.954728/3.06018e-09   1.3126/1.08535e-09
[Falling Waveform]
V_fixture = 2.5V
V_fixture_min = 2.4V
V_fixture_max = 2.6V
R_fixture = 300Ohm
C_fixture = 0F
|   Time   V(typ)   V(min)   V(max)
0s        2.5V       2.4V       2.6V
959.6ps   2.5V       2.4V       2.618V
1.357ns   2.511V     2.4V       1.895V
1.662ns   2.199V     2.4V       1.342V
2.352ns   1.529V     2.327V     795.9mV
2.82ns    1.367V     2.107V     462.4mV
4.133ns   663.9mV    1.689V     418.3mV
5.036ns   584.4mV    1.569V     415.9mV
6.815ns   563.8mV    907.8mV    414.6mV
12.5ns    559.1mV    808.6mV    412.3mV
[Rising Waveform]
V_fixture = 0V
V_fixture_min = 0V
V_fixture_max = 0V
R_fixture = 300Ohm
C_fixture = 0F
|   Time   V(typ)   V(min)   V(max)
0s        -1.827uV   64.96uV    -77.44nV
1.234ns   -32.36mV   -292.9uV   -37.3mV
1.682ns   -47.56mV   -422.9uV   1.183V
1.845ns   21.44mV    -470.1uV   1.352V
2.352ns   903.3mV    -52.6mV    1.928V
2.82ns    1.133V     -25.47mV   2.115V
3.871ns   1.794V     687.8mV    2.157V
4.691ns   1.876V     817.1mV    2.164V
6.078ns   1.904V     1.407V     2.168V
12.5ns    1.917V     1.555V     2.171V
[Rising Waveform]
V_fixture = 2.5V
V_fixture_min = 2.4V
V_fixture_max = 2.6V
R_fixture = 300Ohm
C_fixture = 0F
|   Time   V(typ)   V(min)   V(max)
0s        559mV      808.6mV    412.3mV
816.4ps   559.1mV    806.5mV    420.4mV
1.24ns    573.1mV    805.4mV    1.548V
1.596ns   1.41V      804.5mV    2.355V
2.052ns   2.147V     826.8mV    2.529V
2.208ns   2.295V     1.072V     2.561V
2.488ns   2.421V     1.597V     2.589V
2.759ns   2.445V     1.907V     2.593V
3.732ns   2.489V     2.354V     2.597V
12.5ns    2.5V       2.4V       2.6V
[Falling Waveform]
|Gnd
V_fixture = 0V
V_fixture_min = 0V
V_fixture_max = 0V
R_fixture = 300Ohm
C_fixture = 0F
|   Time   V(typ)   V(min)   V(max)
0s        1.917V     1.555V     2.171V
929.9ps   1.917V     1.556V     2.133V
1.287ns   1.892V     1.557V     1.247V
1.521ns   1.586V     1.557V     469.2mV
1.974ns   718.9mV    1.547V     58.24mV
2.229ns   279.9mV    1.387V     30.35mV
2.483ns   100.8mV    1.151V     10.4mV
3.222ns   18.47mV    280.3mV    2.323mV
3.732ns   9.905mV    59.87mV    2.195mV
12.5ns    697.8nV    64.73uV    -75.72nV
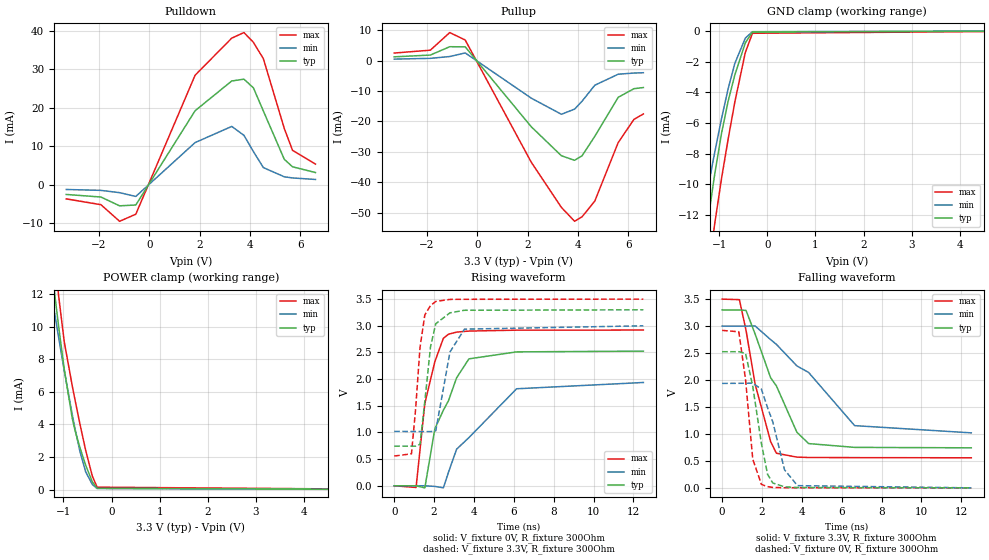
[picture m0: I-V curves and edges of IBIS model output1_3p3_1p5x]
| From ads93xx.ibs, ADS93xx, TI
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|   output1_3p3_1p5x Model
[Model]   output1_3p3_1p5x
Model_type   3-state
Polarity   Non-Inverting
Vmeas = 1.65
Vref = 0
Cref = 2pF
Rref = 100000
|   typ   min   max
C_comp   0.669pF   0.552pF   0.698pF
[Voltage Range]   3.3   3   3.5
[Temperature Range]   27   125   -40
[Pullup Reference]   3.3   3   3.5
[Pulldown Reference]   0   0   0
[Power Clamp Reference]   3.3   3   3.5
[GND Clamp Reference]   0   0   0
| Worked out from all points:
|   slope of the pulldown table from 0 to 0.495 V, typ, clamps not added: 86.2 ohm
|   slope of the pullup table from 0 to 0.495 V, typ, clamps not added: 90.9 ohm
|   GND clamp passes 1 mA (typ) near -0.49 V on its own axis
|   POWER clamp passes 1 mA (typ) near -0.48 V on its own axis
|   falling waveform, V_fixture 3.3V, R_fixture 300Ohm: 20-80 % time 1.75ns typ, 2.93ns min, 1.04ns max; typ from 3.3 V to 0.742 V
|   rising waveform, V_fixture 0V, R_fixture 300Ohm: 20-80 % time 1.35ns typ, 2.35ns min, 787ps max; typ from 0 V to 2.52 V
|   rising waveform, V_fixture 3.3V, R_fixture 300Ohm: 20-80 % time 458ps typ, 588ps min, 381ps max; typ from 0.742 V to 3.3 V
|   falling waveform, V_fixture 0V, R_fixture 300Ohm: 20-80 % time 651ps typ, 868ps min, 463ps max; typ from 2.52 V to 0 V
[Pulldown]
|   Voltage   I(typ)   I(min)   I(max)
-3.3V     -2.497mA   -1.207mA   -3.647mA
-1.924V   -3.163mA   -1.438mA   -5.149mA
-1.181V   -5.445mA   -2.034mA   -9.456mA
-537.9mV  -5.23mA    -3.014mA   -7.617mA
1.818V    19.21mA    10.95mA    28.41mA
3.274V    26.92mA    15.14mA    38.03mA
3.759V    27.39mA    12.83mA    39.47mA
4.135V    25.14mA    8.619mA    36.94mA
4.531V    19.12mA    4.459mA    32.69mA
5.362V    6.614mA    2.085mA    14.6mA
5.689V    4.674mA    1.782mA    8.944mA
6.6V      3.188mA    1.39mA     5.372mA
[GND Clamp]
|   Voltage   I(typ)   I(min)   I(max)
-3.3V     -65.43mA   -48.13mA   -88mA
-1.419V   -16.72mA   -13.4mA    -21.78mA
-1.34V    -14.82mA   -12.03mA   -19.27mA
-1.251V   -12.75mA   -10.51mA   -16.6mA
-1.122V   -9.915mA   -8.368mA   -13.21mA
-1.092V   -9.299mA   -7.887mA   -12.52mA
-953.7mV  -6.687mA   -5.727mA   -9.638mA
-815.1mV  -4.579mA   -3.766mA   -7.051mA
-676.5mV  -2.877mA   -2.123mA   -4.639mA
-458.7mV  -789uA     -478.5uA   -1.416mA
-310.2mV  -80.27uA   -56.11uA   -160.2uA
6.6V      0A         0A         0A
[Pullup]
|   Voltage   I(typ)   I(min)   I(max)
-3.3V     1.244mA    496.4uA    2.488mA
-1.865V   1.825mA    743.7uA    3.438mA
-1.092V   4.576mA    1.345mA    9.23mA
-478.5mV  4.531mA    2.527mA    6.774mA
2.145V    -21.76mA   -12.35mA   -33.43mA
3.343V    -31.31mA   -17.66mA   -48.31mA
3.868V    -32.81mA   -15.96mA   -52.88mA
4.165V    -31.31mA   -13.35mA   -51.38mA
4.67V     -24.91mA   -8.102mA   -46.24mA
5.6V      -12.08mA   -4.478mA   -26.98mA
6.224V    -9.242mA   -4.09mA    -19.35mA
6.6V      -8.863mA   -3.986mA   -17.55mA
[POWER Clamp]
|   Voltage   I(typ)   I(min)   I(max)
-3.3V     74.57mA    53.89mA    103mA
-1.241V   13.49mA    11.88mA    16.28mA
-1.171V   11.74mA    10.61mA    14mA
-1.102V   10.06mA    9.373mA    11.94mA
-983.4mV  7.392mA    7.311mA    9.076mA
-815.1mV  4.344mA    4.58mA     6.342mA
-755.7mV  3.594mA    3.689mA    5.454mA
-656.7mV  2.576mA    2.339mA    4.022mA
-537.9mV  1.498mA    1.095mA    2.414mA
-399.3mV  475.5uA    314.3uA    830.4uA
-300.3mV  81.22uA    66.3uA     149.3uA
6.6V      0A         0A         0A
[Ramp]
R_load = 300
|   typ   min   max
dV/dt_r   1.51508/1.35366e-09   1.16219/2.34695e-09   1.75193/7.87173e-10
dV/dt_f   1.5345/1.74708e-09   1.18819/2.92859e-09   1.76546/1.03825e-09
[Falling Waveform]
V_fixture = 3.3V
V_fixture_min = 3V
V_fixture_max = 3.5V
R_fixture = 300Ohm
C_fixture = 0F
|   Time   V(typ)   V(min)   V(max)
0s        3.3V       3V         3.5V
867.7ps   3.299V     3V         3.49V
1.2ns     3.29V      3V         2.921V
1.656ns   2.853V     3.002V     1.922V
2.434ns   2.042V     2.749V     858.8mV
2.721ns   1.892V     2.662V     642.4mV
3.75ns    1.032V     2.262V     570mV
4.34ns    821.3mV    2.14V      563.1mV
6.648ns   750.6mV    1.154V     560.8mV
12.5ns    742.5mV    1.02V      557.6mV
[Rising Waveform]
V_fixture = 0V
V_fixture_min = 0V
V_fixture_max = 0V
R_fixture = 300Ohm
C_fixture = 0F
|   Time   V(typ)   V(min)   V(max)
0s        754.7nV    54.15uV    -240.4nV
1.098ns   -29.39uV   -27.03uV   -31.9mV
1.537ns   -38.89mV   -59.46uV   1.545V
2.039ns   1.068V     -11.66mV   2.328V
2.467ns   1.418V     -37.33mV   2.765V
2.721ns   1.594V     251.8mV    2.842V
3.13ns    2.025V     686.1mV    2.882V
3.75ns    2.38V      904.3mV    2.901V
6.14ns    2.511V     1.819V     2.918V
12.5ns    2.525V     1.937V     2.92V
[Rising Waveform]
V_fixture = 3.3V
V_fixture_min = 3V
V_fixture_max = 3.5V
R_fixture = 300Ohm
C_fixture = 0F
|   Time   V(typ)   V(min)   V(max)
0s        742.5mV    1.02V      557.6mV
867.7ps   742.5mV    1.018V     599.5mV
1.076ns   742.6mV    1.018V     1.446V
1.294ns   779.5mV    1.017V     2.592V
1.537ns   1.587V     1.017V     3.205V
1.824ns   2.613V     1.016V     3.38V
2.085ns   3.039V     1.031V     3.456V
2.799ns   3.243V     2.511V     3.495V
3.526ns   3.291V     2.937V     3.497V
12.5ns    3.3V       3V         3.5V
[Falling Waveform]
|Gnd
V_fixture = 0V
V_fixture_min = 0V
V_fixture_max = 0V
R_fixture = 300Ohm
C_fixture = 0F
|   Time   V(typ)   V(min)   V(max)
0s        2.525V     1.937V     2.92V
838.7ps   2.525V     1.939V     2.895V
1.177ns   2.493V     1.94V      2.004V
1.537ns   1.882V     1.941V     533.8mV
1.971ns   821.9mV    1.829V     63.85mV
2.282ns   249.2mV    1.486V     23.28mV
2.542ns   89.92mV    1.223V     7.345mV
3.13ns    19.49mV    336mV      2.351mV
3.781ns   6.242mV    40.95mV    2.188mV
12.5ns    399.2nV    56.32uV    -186.8nV
